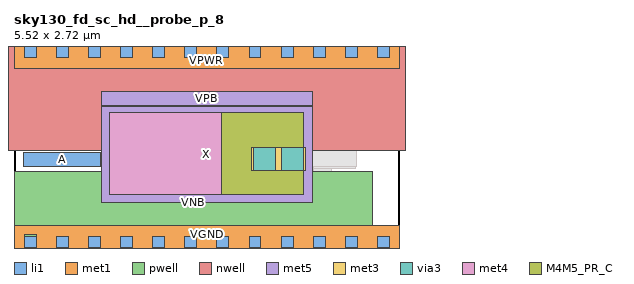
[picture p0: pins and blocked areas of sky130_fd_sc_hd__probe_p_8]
MACRO sky130_fd_sc_hd__probe_p_8
  CLASS CORE ;
  FOREIGN sky130_fd_sc_hd__probe_p_8 ;
  ORIGIN 0.000 0.000 ;
  SIZE 5.520 BY 2.720 ;
  SYMMETRY X Y R90 ;
  SITE unithd ;
  PIN A
    DIRECTION INPUT ;
    USE SIGNAL ;
    PORT
      LAYER li1 ;
        RECT 0.140 1.075 1.240 1.275 ;
    END
  END A
  PIN VGND
    DIRECTION INOUT ;
    USE GROUND ;
    SHAPE ABUTMENT ;
    PORT
      LAYER li1 ;
        RECT 0.145 -0.085 0.315 0.085 ;
        RECT 0.605 -0.085 0.775 0.085 ;
        RECT 1.065 -0.085 1.235 0.085 ;
        RECT 1.525 -0.085 1.695 0.085 ;
        RECT 1.985 -0.085 2.155 0.085 ;
        RECT 2.445 -0.085 2.615 0.085 ;
        RECT 2.905 -0.085 3.075 0.085 ;
        RECT 3.365 -0.085 3.535 0.085 ;
        RECT 3.825 -0.085 3.995 0.085 ;
        RECT 4.285 -0.085 4.455 0.085 ;
        RECT 4.745 -0.085 4.915 0.085 ;
        RECT 5.205 -0.085 5.375 0.085 ;
      LAYER met1 ;
        RECT 0.000 -0.240 5.520 0.240 ;
    END
  END VGND
  PIN VNB
    DIRECTION INOUT ;
    USE GROUND ;
    PORT
      LAYER pwell ;
        RECT 0.005 0.105 5.135 1.015 ;
        RECT 0.150 -0.085 0.320 0.105 ;
    END
  END VNB
  PIN VPB
    DIRECTION INOUT ;
    USE POWER ;
    PORT
      LAYER nwell ;
        RECT -0.190 1.305 5.710 2.910 ;
    END
  END VPB
  PIN VPWR
    DIRECTION INOUT ;
    USE POWER ;
    SHAPE ABUTMENT ;
    PORT
      LAYER li1 ;
        RECT 0.145 2.635 0.315 2.805 ;
        RECT 0.605 2.635 0.775 2.805 ;
        RECT 1.065 2.635 1.235 2.805 ;
        RECT 1.525 2.635 1.695 2.805 ;
        RECT 1.985 2.635 2.155 2.805 ;
        RECT 2.445 2.635 2.615 2.805 ;
        RECT 2.905 2.635 3.075 2.805 ;
        RECT 3.365 2.635 3.535 2.805 ;
        RECT 3.825 2.635 3.995 2.805 ;
        RECT 4.285 2.635 4.455 2.805 ;
        RECT 4.745 2.635 4.915 2.805 ;
        RECT 5.205 2.635 5.375 2.805 ;
      LAYER met1 ;
        RECT 0.000 2.480 5.520 2.960 ;
    END
  END VPWR
  PIN X
    DIRECTION OUTPUT ;
    USE SIGNAL ;
    PORT
      LAYER met5 ;
        RECT 1.250 1.950 4.270 2.160 ;
    END
    PORT
      LAYER met3 ;
        RECT 3.395 1.025 4.175 1.355 ;
      LAYER via3 ;
        RECT 3.425 1.030 3.745 1.350 ;
        RECT 3.825 1.030 4.145 1.350 ;
      LAYER met4 ;
        RECT 1.370 0.680 4.150 1.860 ;
      LAYER M4M5_PR_C ;
        RECT 2.970 0.680 4.150 1.860 ;
      LAYER met5 ;
        RECT 1.250 0.560 4.270 1.945 ;
    END
  END X
  OBS
      LAYER li1 ;
        RECT 0.000 2.635 0.145 2.805 ;
        RECT 0.315 2.635 0.605 2.805 ;
        RECT 0.775 2.635 1.065 2.805 ;
        RECT 1.235 2.635 1.525 2.805 ;
        RECT 1.695 2.635 1.985 2.805 ;
        RECT 2.155 2.635 2.445 2.805 ;
        RECT 2.615 2.635 2.905 2.805 ;
        RECT 3.075 2.635 3.365 2.805 ;
        RECT 3.535 2.635 3.825 2.805 ;
        RECT 3.995 2.635 4.285 2.805 ;
        RECT 4.455 2.635 4.745 2.805 ;
        RECT 4.915 2.635 5.205 2.805 ;
        RECT 5.375 2.635 5.520 2.805 ;
        RECT 0.095 1.615 0.425 2.465 ;
        RECT 0.595 1.835 0.765 2.635 ;
        RECT 0.935 1.615 1.265 2.465 ;
        RECT 1.435 1.835 1.605 2.635 ;
        RECT 1.855 1.615 2.025 2.465 ;
        RECT 2.195 1.835 2.525 2.635 ;
        RECT 2.695 1.615 2.865 2.465 ;
        RECT 3.035 1.835 3.365 2.635 ;
        RECT 3.535 1.615 3.705 2.465 ;
        RECT 3.875 1.835 4.205 2.635 ;
        RECT 4.375 1.615 4.545 2.465 ;
        RECT 0.095 1.445 1.595 1.615 ;
        RECT 1.855 1.445 4.545 1.615 ;
        RECT 4.715 1.485 5.045 2.635 ;
        RECT 1.420 1.245 1.595 1.445 ;
        RECT 4.290 1.315 4.545 1.445 ;
        RECT 1.420 1.075 4.045 1.245 ;
        RECT 1.420 0.905 1.595 1.075 ;
        RECT 4.290 1.055 4.885 1.315 ;
        RECT 4.290 0.905 4.545 1.055 ;
        RECT 0.175 0.735 1.595 0.905 ;
        RECT 1.855 0.735 4.545 0.905 ;
        RECT 0.175 0.255 0.345 0.735 ;
        RECT 0.515 0.085 0.845 0.565 ;
        RECT 1.015 0.260 1.185 0.735 ;
        RECT 1.355 0.085 1.685 0.565 ;
        RECT 1.855 0.255 2.025 0.735 ;
        RECT 2.195 0.085 2.525 0.565 ;
        RECT 2.695 0.255 2.865 0.735 ;
        RECT 3.035 0.085 3.365 0.565 ;
        RECT 3.535 0.255 3.705 0.735 ;
        RECT 3.875 0.085 4.205 0.565 ;
        RECT 4.375 0.255 4.545 0.735 ;
        RECT 4.715 0.085 5.045 0.885 ;
        RECT 0.000 -0.085 0.145 0.085 ;
        RECT 0.315 -0.085 0.605 0.085 ;
        RECT 0.775 -0.085 1.065 0.085 ;
        RECT 1.235 -0.085 1.525 0.085 ;
        RECT 1.695 -0.085 1.985 0.085 ;
        RECT 2.155 -0.085 2.445 0.085 ;
        RECT 2.615 -0.085 2.905 0.085 ;
        RECT 3.075 -0.085 3.365 0.085 ;
        RECT 3.535 -0.085 3.825 0.085 ;
        RECT 3.995 -0.085 4.285 0.085 ;
        RECT 4.455 -0.085 4.745 0.085 ;
        RECT 4.915 -0.085 5.205 0.085 ;
        RECT 5.375 -0.085 5.520 0.085 ;
      LAYER met1 ;
        RECT 3.465 1.305 4.105 1.320 ;
        RECT 3.465 1.075 4.910 1.305 ;
        RECT 3.465 1.060 4.105 1.075 ;
      LAYER met2 ;
        RECT 3.445 1.005 4.125 1.375 ;
  END
END sky130_fd_sc_hd__probe_p_8
